! (c) 2009  Infineon Technologies AG, Munich
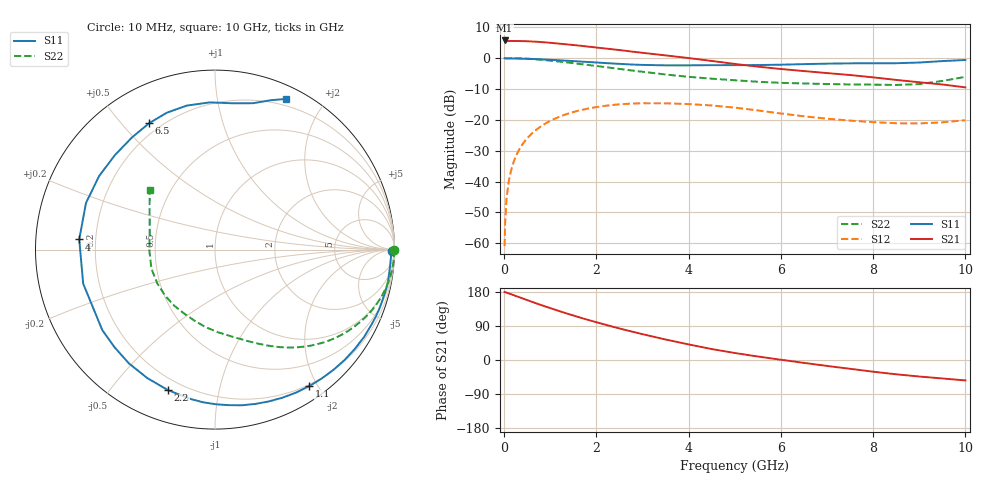
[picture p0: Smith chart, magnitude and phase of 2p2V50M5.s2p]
! Infineon Technologies  Discrete & RF Semiconductors
! BFP420
! VCE =  2.5 V,  IC =  0.5 mA
! Common Emitter S-Parameters:  Nov 2009
# GHz  S  MA  R  50
!  f  S11  S21  S12  S22
! GHz  MAG  ANG  MAG  ANG  MAG  ANG  MAG  ANG
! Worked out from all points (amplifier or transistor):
!   46 points, 10 MHz to 10 GHz, reference 50 ohm
!   highest |S21| = 5.7 dB at 10 MHz (marker M1)
!   |S21| within 3 dB of that: start of sweep to 2.435 GHz
!   unconditionally stable (mu >= 1): 4.431 GHz to end of sweep
!   at 300 MHz: K = 0.02, MSG = 17.9 dB, |S12| = -30.4 dB
!   at 1.7 GHz: K = 0.27, MSG = 10.3 dB, |S12| = -16.8 dB
!   at 10 GHz: K = 1.58, MAG = 0.9 dB, |S12| = -20.2 dB
!   lowest NFmin = 0.68 dB at 900 MHz
!   S11 on the Smith chart (normalised r, x): 10 MHz: open; 1.1 GHz: 0.18, -1.89; 2.2 GHz: 0.14, -0.71; 4 GHz: 0.14, +0.04; 6.5 GHz: 0.16, +0.60; 10 GHz: 0.13, +1.56
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0.01  0.9859 -0.5  1.918 179.4  0.0009 95.7  0.9991 -0.1
0.02  0.9811 -1.0  1.857 179.5  0.002 89.4  0.9983 -0.5
0.05  0.9813 -2.4  1.862 177.9  0.0052 88.2  0.9983 -1.4
0.1  0.9798 -5.1  1.882 175.8  0.0101 87.5  0.998 -2.8
0.15  0.9794 -7.5  1.883 173.6  0.0151 85.5  0.9964 -4.2
0.25  0.9787 -12.5  1.876 169.0  0.0252 82.4  0.992 -7.0
0.4  0.9731 -20.1  1.871 162.5  0.0403 77.5  0.9811 -11.1
0.6  0.9629 -30.3  1.845 153.6  0.0598 71.0  0.9606 -16.5
0.9  0.9403 -45.5  1.783 140.9  0.0873 61.3  0.9198 -24.0
1.1  0.9241 -55.5  1.729 132.9  0.104 55.1  0.8886 -28.7
1.4  0.8974 -70.5  1.646 121.1  0.1266 45.9  0.8394 -35.3
1.7  0.8699 -85.0  1.562 110.1  0.1453 37.2  0.7893 -41.3
2.2  0.8259 -108.4  1.42 93.0  0.1682 23.6  0.7093 -50.2
2.8  0.7805 -135.9  1.259 74.1  0.1828 8.4  0.6222 -59.8
3.5  0.7585 -165.5  1.099 54.1  0.1844 -7.1  0.5396 -70.6
4  0.7586 175.7  0.996 41.1  0.1793 -16.3  0.4948 -78.7
4.5  0.7643 160.1  0.894 28.9  0.1701 -24.8  0.4615 -87.7
5.5  0.767 136.6  0.723 9.2  0.1415 -37.3  0.4118 -106.1
6.5  0.7942 117.5  0.613 -7.6  0.1137 -41.9  0.386 -126.2
7  0.8084 109.4  0.569 -15.7  0.1039 -41.4  0.3783 -137.2
8.5  0.8211 83.1  0.441 -37.7  0.0877 -34.1  0.3653 -178.5
10  0.9267 64.9  0.334 -53.9  0.0982 -22.3  0.4943 137.4
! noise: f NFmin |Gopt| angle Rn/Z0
0.9  0.68  0.78  35  0.65
1.8  1.42  0.6  75  0.5
2.4  1.57  0.58  98  0.37
3  2.1  0.58  128  0.24
4  2.49  0.57  177  0.09
